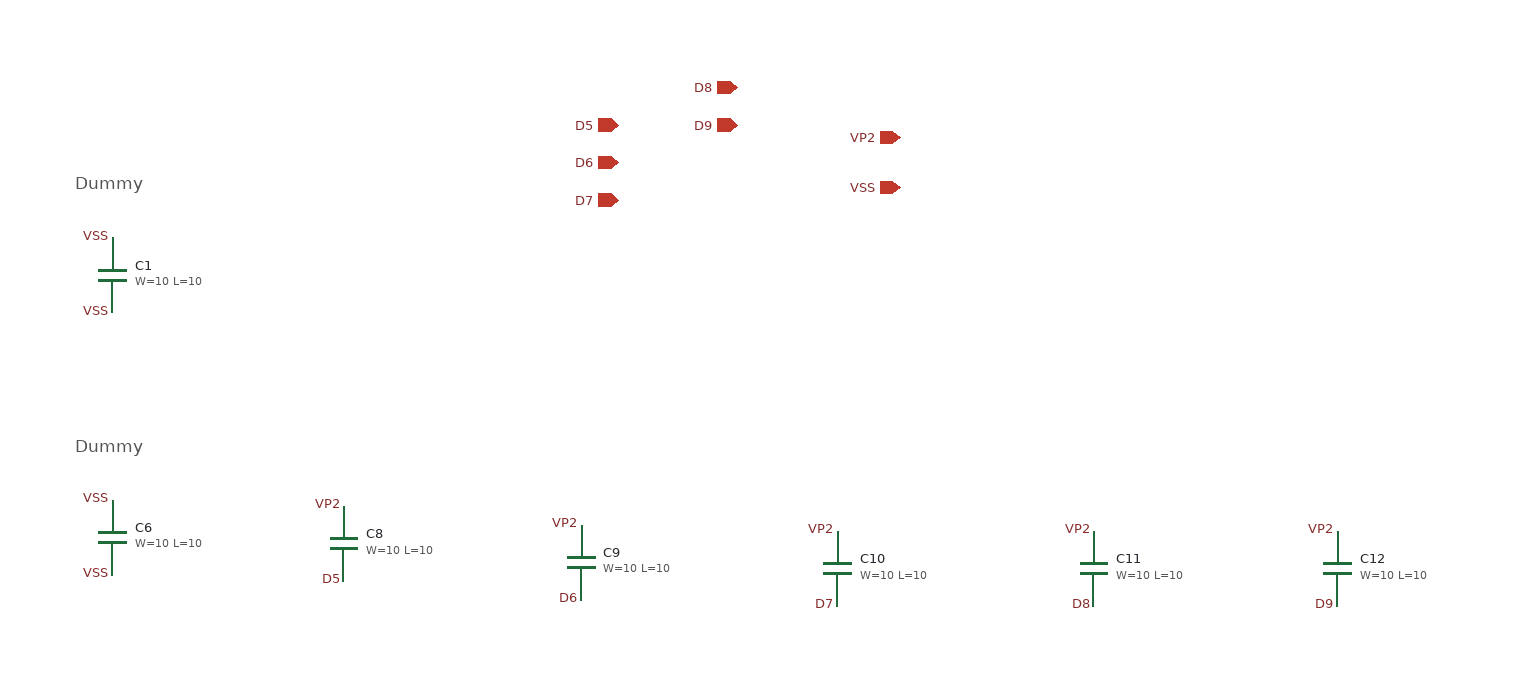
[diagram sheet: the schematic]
v {xschem version=3.1.0 file_version=1.2
}
G {}
K {}
V {}
S {}
E {}
T {Dummy} 430 -760 0 0 0.4 0.4 {}
T {Dummy} 430 -970 0 0 0.4 0.4 {}
C {sky130_fd_pr/cap_mim_m3_1.sym} 645 -670 0 0 {name=C8 model=cap_mim_m3_1 W=10 L=10 MF=1 spiceprefix=X}
C {devices/lab_pin.sym} 645 -640 3 0 {name=p82 sig_type=std_logic lab=D5}
C {sky130_fd_pr/cap_mim_m3_1.sym} 835 -655 0 0 {name=C9 model=cap_mim_m3_1 W=10 L=10 MF=2 spiceprefix=X}
C {devices/lab_pin.sym} 835 -625 3 0 {name=p85 sig_type=std_logic lab=D6}
C {sky130_fd_pr/cap_mim_m3_1.sym} 1040 -650 0 0 {name=C10 model=cap_mim_m3_1 W=10 L=10 MF=4 spiceprefix=X}
C {devices/lab_pin.sym} 1040 -620 3 0 {name=p95 sig_type=std_logic lab=D7}
C {sky130_fd_pr/cap_mim_m3_1.sym} 1245 -650 0 0 {name=C11 model=cap_mim_m3_1 W=10 L=10 MF=8 spiceprefix=X}
C {devices/lab_pin.sym} 1245 -620 3 0 {name=p105 sig_type=std_logic lab=D8}
C {sky130_fd_pr/cap_mim_m3_1.sym} 1440 -650 0 0 {name=C12 model=cap_mim_m3_1 W=10 L=10 MF=16 spiceprefix=X}
C {devices/lab_pin.sym} 1440 -680 0 0 {name=p114 sig_type=std_logic lab=VP2}
C {devices/lab_pin.sym} 1440 -620 3 0 {name=p115 sig_type=std_logic lab=D9}
C {devices/ipin.sym} 1090 -995 0 0 {name=p8 lab=VP2}
C {devices/ipin.sym} 1090 -955 0 0 {name=p11 lab=VSS}
C {devices/lab_pin.sym} 1245 -680 0 0 {name=p15 sig_type=std_logic lab=VP2}
C {devices/lab_pin.sym} 1040 -680 0 0 {name=p16 sig_type=std_logic lab=VP2}
C {devices/lab_pin.sym} 835 -685 0 0 {name=p17 sig_type=std_logic lab=VP2}
C {devices/lab_pin.sym} 645 -700 0 0 {name=p18 sig_type=std_logic lab=VP2}
C {devices/ipin.sym} 865 -1005 0 0 {name=p24 lab=D5}
C {devices/ipin.sym} 865 -975 0 0 {name=p25 lab=D6}
C {devices/ipin.sym} 865 -945 0 0 {name=p26 lab=D7}
C {devices/ipin.sym} 960 -1035 0 0 {name=p27 lab=D8}
C {devices/ipin.sym} 960 -1005 0 0 {name=p28 lab=D9}
C {sky130_fd_pr/cap_mim_m3_1.sym} 460 -675 0 0 {name=C6 model=cap_mim_m3_1 W=10 L=10 MF=1 spiceprefix=X}
C {devices/lab_pin.sym} 460 -705 0 0 {name=p29 sig_type=std_logic lab=VSS}
C {devices/lab_pin.sym} 460 -645 3 0 {name=p30 sig_type=std_logic lab=VSS}
C {sky130_fd_pr/cap_mim_m3_1.sym} 460 -885 0 0 {name=C1 model=cap_mim_m3_1 W=10 L=10 MF=32 spiceprefix=X}
C {devices/lab_pin.sym} 460 -915 0 0 {name=p1 sig_type=std_logic lab=VSS}
C {devices/lab_pin.sym} 460 -855 3 0 {name=p2 sig_type=std_logic lab=VSS}
